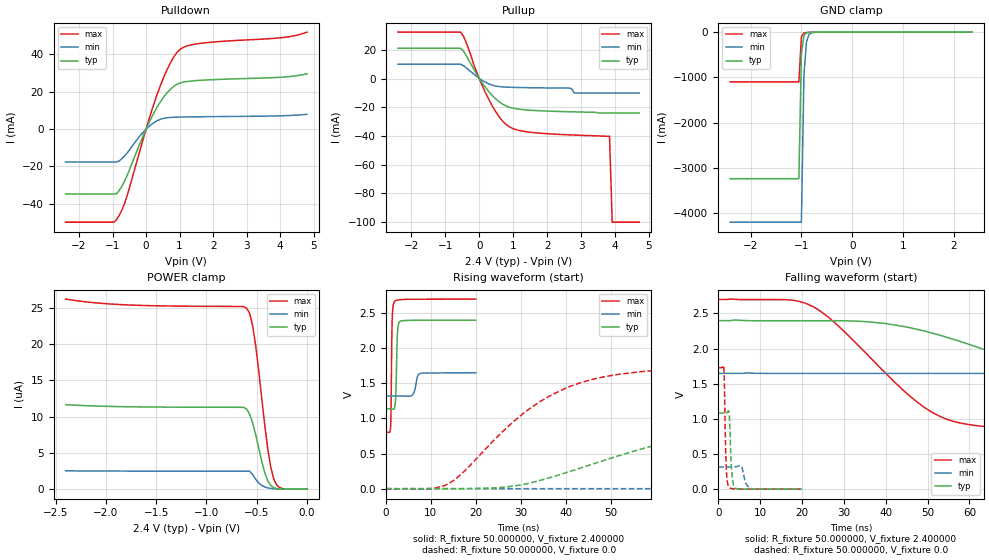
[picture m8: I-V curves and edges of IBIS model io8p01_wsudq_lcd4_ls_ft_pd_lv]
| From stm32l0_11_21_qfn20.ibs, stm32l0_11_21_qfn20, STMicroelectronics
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|   Model io8p01_wsudq_lcd4_ls_ft_pd_lv
[Model]  io8p01_wsudq_lcd4_ls_ft_pd_lv
Model_type I/O
Polarity   Non-Inverting
Enable   Active-Low
Vinl =   0.720000V
Vinh =   1.680000V
Vmeas =  1.200000V
Cref =   50.000000pF
Rref =   100.000000M
Vref =   0.0V
C_comp   3.178800pF   3.170000pF   3.206700pF
[Temperature Range]   25.000000   0.105000k   -40.000000
[Pullup Reference]   2.400000V   1.650000V   2.700000V
[Pulldown Reference]   0.0V   0.0V   0.0V
[POWER Clamp Reference]   2.400000V   1.650000V   2.700000V
[GND Clamp Reference]   0.0V   0.0V   0.0V
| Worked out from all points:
|   slope of the pulldown table from 0 to 0.36 V, typ, clamps not added: 28.5 ohm
|   slope of the pullup table from 0 to 0.36 V, typ, clamps not added: 32.2 ohm
|   GND clamp passes 1 mA (typ) near -0.64 V on its own axis
|   rising waveform, R_fixture 50.000000, V_fixture 2.400000: 20-80 % time 296ps typ, 647ps min, 211ps max; typ from 1.14 V to 2.4 V
|   rising waveform, R_fixture 50.000000, V_fixture 0.0: 20-80 % time 39.6ns typ, 107ns min, 19.4ns max; typ from 0 V to 1.08 V
|   falling waveform, R_fixture 50.000000, V_fixture 2.400000: 20-80 % time 40.7ns typ, 106ns min, 20.1ns max; typ from 2.4 V to 1.14 V
|   falling waveform, R_fixture 50.000000, V_fixture 0.0: 20-80 % time 489ps typ, 855ps min, 389ps max; typ from 1.08 V to 0 V
[Pulldown]
|Voltage   I(typ)   I(min)   I(max)
-2.4V     -34.71mA   -17.6mA    -49.82mA
-960mV    -34.71mA   -17.6mA    -49.82mA
-880mV    -34.55mA   -17.6mA    -48.46mA
-720mV    -30.52mA   -15.8mA    -43.27mA
-560mV    -24.65mA   -12.68mA   -35.33mA
0V        326fA      0A         10fA
400mV     13.84mA    5.066mA    22.03mA
720mV     21.25mA    6.254mA    35.26mA
1.04V     24.83mA    6.464mA    43.03mA
1.6V      26.11mA    6.627mA    45.88mA
4V        27.76mA    7.125mA    48.88mA
4.8V      29.63mA    7.94mA     51.96mA
[Pullup]
|Voltage   I(typ)   I(min)   I(max)
-2.4V     21.06mA    9.988mA    32.35mA
-560mV    21.06mA    9.988mA    32.35mA
-400mV    16.53mA    7.734mA    25.89mA
-80mV     3.011mA    1.498mA    4.671mA
320mV     -10.16mA   -4.078mA   -16.34mA
640mV     -17.08mA   -5.718mA   -28.28mA
960mV     -20.45mA   -6.129mA   -34.5mA
1.76V     -22.39mA   -6.471mA   -37.97mA
2.8V      -23.2mA    -10mA      -39.35mA
3.84V     -24mA      -10mA      -40.2mA
3.92V     -24mA      -10mA      -100mA
4.72V     -24mA      -10mA      -100mA
[GND_clamp]
|Voltage   I(typ)   I(min)   I(max)
-2.4V     -3.238A    -4.199A    -1.101A
-1.05V    -3.238A    -4.199A    -1.101A
-1V       -476.5mA   -4.199A    -104.7mA
-950mV    -76.69mA   -936.1mA   -18.75mA
-900mV    -16.87mA   -213.2mA   -9.366mA
-850mV    -6.718mA   -51.14mA   -6.786mA
-800mV    -4.121mA   -13.93mA   -5.004mA
-650mV    -1.082mA   -1.228mA   -1.183mA
2.35V     52.69uA    50.02uA    36.84uA
[POWER_clamp]
|Voltage   I(typ)   I(min)   I(max)
-2.4V     11.64uA    2.527uA    26.18uA
-1.86V    11.37uA    2.49uA     25.43uA
-600mV    11.04uA    2.475uA    24.9uA
-570mV    10.3uA     2.473uA    24.21uA
-540mV    9.097uA    2.001uA    22.48uA
-510mV    7.497uA    1.351uA    19.73uA
-450mV    3.846uA    513.2nA    12.52uA
-390mV    1.155uA    176.1nA    5.528uA
-360mV    508.6nA    103.4nA    2.997uA
-330mV    204.7nA    61.05nA    1.375uA
-270mV    0A         0A         195.3nA
0V        0A         0A         0A
[Ramp]
| variable   typ   min   max
dV/dt_r  0.65004/39.56398n   0.18943/0.10636u   1.03746/19.40040n
dV/dt_f  0.75702/40.69247n   0.19512/0.10579u   1.13800/20.04625n
R_load = 50.000000
[Rising Waveform]
R_fixture= 50.000000
V_fixture= 2.400000
V_fixture_min= 1.650000
V_fixture_max= 2.700000
|time   V(typ)   V(min)   V(max)
0s        1.137V     1.32V      802.9mV
1.041ns   1.137V     1.32V      868.5mV
1.161ns   1.136V     1.32V      1.174V
1.401ns   1.133V     1.32V      2.39V
1.882ns   1.147V     1.32V      2.66V
2.202ns   1.333V     1.32V      2.678V
2.603ns   2.24V      1.32V      2.685V
3.043ns   2.375V     1.32V      2.689V
7.648ns   2.398V     1.64V      2.697V
19.94ns   2.399V     1.649V     2.7V
[Rising Waveform]
R_fixture= 50.000000
V_fixture= 0.0
V_fixture_min= 0.0
V_fixture_max= 0.0
|time   V(typ)   V(min)   V(max)
0s        1.509nV    7.606nV    1.259nV
14.01ns   -210.7uV   -47.3uV    75.73mV
30.03ns   54.15mV    -45.9uV    1.046V
40.04ns   228.6mV    -45.83uV   1.434V
49.05ns   414.9mV    -40.6uV    1.6V
64.06ns   686.2mV    35.21uV    1.698V
87.09ns   930.5mV    1.179mV    1.726V
126.1ns   1.057V     45.09mV    1.729V
255.3ns   1.083V     267mV      1.729V
498.5ns   1.083V     316.1mV    1.729V
[Falling Waveform]
R_fixture= 50.000000
V_fixture= 2.400000
V_fixture_min= 1.650000
V_fixture_max= 2.700000
|time   V(typ)   V(min)   V(max)
0s        2.399V     1.649V     2.7V
21.02ns   2.397V     1.648V     2.642V
27.03ns   2.397V     1.648V     2.411V
51.05ns   2.221V     1.648V     1.095V
58.06ns   2.097V     1.648V     939mV
71.07ns   1.825V     1.648V     856.4mV
99.1ns    1.361V     1.647V     814.4mV
136.1ns   1.2V       1.633V     804.7mV
288.3ns   1.138V     1.378V     802.8mV
498.5ns   1.137V     1.32V      802.9mV
[Falling Waveform]
R_fixture= 50.000000
V_fixture= 0.0
V_fixture_min= 0.0
V_fixture_max= 0.0
|time   V(typ)   V(min)   V(max)
0s        1.083V     316.1mV    1.729V
1.321ns   1.083V     316.1mV    1.745V
1.441ns   1.083V     316.1mV    1.593V
1.722ns   1.083V     316.1mV    696.1mV
1.922ns   1.083V     316.1mV    321mV
2.563ns   1.097V     316.1mV    31.39mV
3.203ns   276.4mV    315.9mV    8.634mV
3.924ns   23.58mV    315.8mV    4.338mV
7.928ns   928.8uV    8.831mV    765.5uV
19.94ns   1.509nV    7.606nV    1.259nV
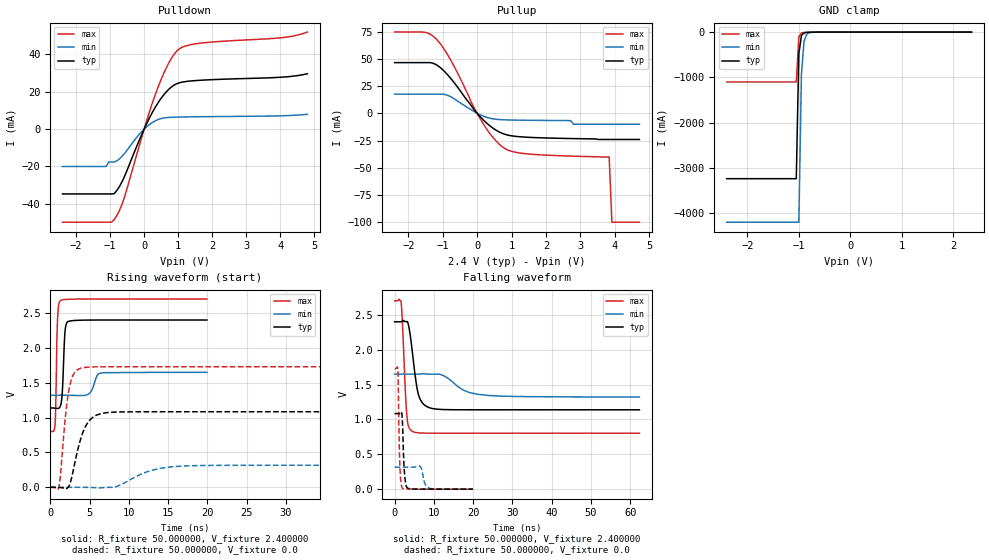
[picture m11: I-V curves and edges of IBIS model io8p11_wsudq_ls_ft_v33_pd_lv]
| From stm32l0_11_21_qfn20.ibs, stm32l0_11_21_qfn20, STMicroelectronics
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|   Model io8p11_wsudq_ls_ft_v33_pd_lv
[Model]  io8p11_wsudq_ls_ft_v33_pd_lv
Model_type I/O
Polarity   Non-Inverting
Enable   Active-Low
Vinl =   0.720000V
Vinh =   1.680000V
Vmeas =  1.200000V
Cref =   50.000000pF
Rref =   100.000000M
Vref =   0.0V
C_comp   2.582000pF   2.574200pF   2.601000pF
[Temperature Range]   25.000000   0.105000k   -40.000000
[Pullup Reference]   2.400000V   1.650000V   2.700000V
[Pulldown Reference]   0.0V   0.0V   0.0V
[POWER Clamp Reference]   2.400000V   1.650000V   2.700000V
[GND Clamp Reference]   0.0V   0.0V   0.0V
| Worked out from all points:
|   slope of the pulldown table from 0 to 0.36 V, typ, clamps not added: 28.5 ohm
|   slope of the pullup table from 0 to 0.36 V, typ, clamps not added: 32.2 ohm
|   GND clamp passes 1 mA (typ) near -0.64 V on its own axis
|   rising waveform, R_fixture 50.000000, V_fixture 2.400000: 20-80 % time 280ps typ, 635ps min, 195ps max; typ from 1.14 V to 2.4 V
|   rising waveform, R_fixture 50.000000, V_fixture 0.0: 20-80 % time 1.58ns typ, 3.84ns min, 927ps max; typ from 0 V to 1.08 V
|   falling waveform, R_fixture 50.000000, V_fixture 2.400000: 20-80 % time 1.8ns typ, 5.35ns min, 920ps max; typ from 2.4 V to 1.14 V
|   falling waveform, R_fixture 50.000000, V_fixture 0.0: 20-80 % time 480ps typ, 860ps min, 379ps max; typ from 1.08 V to 0 V
[Pulldown]
|Voltage   I(typ)   I(min)   I(max)
-2.4V     -34.7mA    -20mA      -49.82mA
-1.12V    -34.7mA    -20mA      -49.82mA
-1.04V    -34.7mA    -17.6mA    -49.82mA
-880mV    -34.55mA   -17.6mA    -48.46mA
-560mV    -24.65mA   -12.68mA   -35.33mA
0V        0A         0A         142fA
400mV     13.84mA    5.066mA    22.03mA
720mV     21.25mA    6.254mA    35.26mA
1.04V     24.83mA    6.464mA    43.03mA
1.6V      26.11mA    6.627mA    45.88mA
4V        27.76mA    7.125mA    48.88mA
4.8V      29.64mA    7.94mA     51.96mA
[Pullup]
|Voltage   I(typ)   I(min)   I(max)
-2.4V     46.57mA    17.61mA    74.62mA
-1.52V    46.57mA    17.61mA    74.5mA
-1.2V     44.84mA    17.61mA    68.61mA
-720mV    30.25mA    14.38mA    46.12mA
-160mV    6.59mA     3.051mA    9.467mA
160mV     -5.477mA   -2.361mA   -8.695mA
480mV     -14.04mA   -5.167mA   -22.91mA
800mV     -19.2mA    -5.978mA   -32.18mA
1.52V     -22.07mA   -6.4mA     -37.42mA
3.84V     -24mA      -10mA      -40.2mA
3.92V     -24mA      -10mA      -100mA
4.72V     -24mA      -10mA      -100mA
[GND_clamp]
|Voltage   I(typ)   I(min)   I(max)
-2.4V     -3.237A    -4.198A    -1.1A
-1.05V    -3.237A    -4.198A    -1.1A
-1V       -475.9mA   -4.198A    -104.3mA
-950mV    -76.38mA   -935.5mA   -18.57mA
-900mV    -16.78mA   -213mA     -9.302mA
-850mV    -6.726mA   -51.1mA    -6.732mA
-800mV    -4.12mA    -13.96mA   -4.933mA
-650mV    -1.06mA    -1.216mA   -1.157mA
2.35V     52.69uA    50.02uA    36.84uA
[POWER_clamp]
|Voltage   I(typ)   I(min)   I(max)
-2.4V     0A         0A         0A
0V        0A         0A         0A
[Ramp]
| variable   typ   min   max
dV/dt_r  0.65004/1.58142n   0.18967/3.83286n   1.03746/0.92421n
dV/dt_f  0.75702/1.79282n   0.19608/5.34124n   1.13800/0.91715n
R_load = 50.000000
[Rising Waveform]
R_fixture= 50.000000
V_fixture= 2.400000
V_fixture_min= 1.650000
V_fixture_max= 2.700000
|time   V(typ)   V(min)   V(max)
0s        1.138V     1.32V      802.3mV
600.6ps   1.135V     1.32V      888.6mV
920.9ps   1.131V     1.32V      2.404V
1.281ns   1.164V     1.32V      2.677V
1.522ns   1.346V     1.32V      2.688V
1.882ns   2.24V      1.32V      2.694V
2.242ns   2.377V     1.32V      2.696V
4.925ns   2.398V     1.343V     2.699V
6.527ns   2.399V     1.639V     2.7V
19.94ns   2.399V     1.649V     2.7V
[Rising Waveform]
R_fixture= 50.000000
V_fixture= 0.0
V_fixture_min= 0.0
V_fixture_max= 0.0
|time   V(typ)   V(min)   V(max)
0s        -26.59uV   958.5nV    234.2uV
1.126ns   -1.191mV   -12.66uV   25.04mV
2.002ns   -25.52mV   72.77uV    1.096V
2.377ns   16.96mV    80.17uV    1.399V
3.003ns   284.6mV    83.36uV    1.629V
4.004ns   740mV      -148.7uV   1.711V
5.506ns   1.011V     -3.767mV   1.726V
8.383ns   1.079V     9.917mV    1.729V
17.14ns   1.083V     306.6mV    1.729V
62.31ns   1.083V     316.1mV    1.729V
[Falling Waveform]
R_fixture= 50.000000
V_fixture= 2.400000
V_fixture_min= 1.650000
V_fixture_max= 2.700000
|time   V(typ)   V(min)   V(max)
0s        2.399V     1.649V     2.7V
1.627ns   2.398V     1.649V     2.697V
1.877ns   2.402V     1.649V     2.511V
2.753ns   2.402V     1.649V     1.39V
3.128ns   2.402V     1.649V     1.046V
4.505ns   1.972V     1.649V     829.1mV
6.256ns   1.322V     1.648V     806.7mV
9.134ns   1.162V     1.648V     802.7mV
21.4ns    1.138V     1.358V     802.3mV
62.31ns   1.138V     1.32V      802.3mV
[Falling Waveform]
R_fixture= 50.000000
V_fixture= 0.0
V_fixture_min= 0.0
V_fixture_max= 0.0
|time   V(typ)   V(min)   V(max)
0s        1.083V     316.1mV    1.729V
800.8ps   1.083V     316.1mV    1.719V
1.161ns   1.083V     316.1mV    708.2mV
1.361ns   1.088V     316.1mV    316.8mV
1.962ns   999.4mV    316.1mV    13.93mV
2.482ns   257.6mV    316.1mV    3.827mV
3.203ns   21.53mV    316.1mV    2.144mV
6.567ns   733.6uV    325mV      309.2uV
9.249ns   118.8uV    5.908mV    239.1uV
19.94ns   -26.59uV   958.5nV    234.2uV
